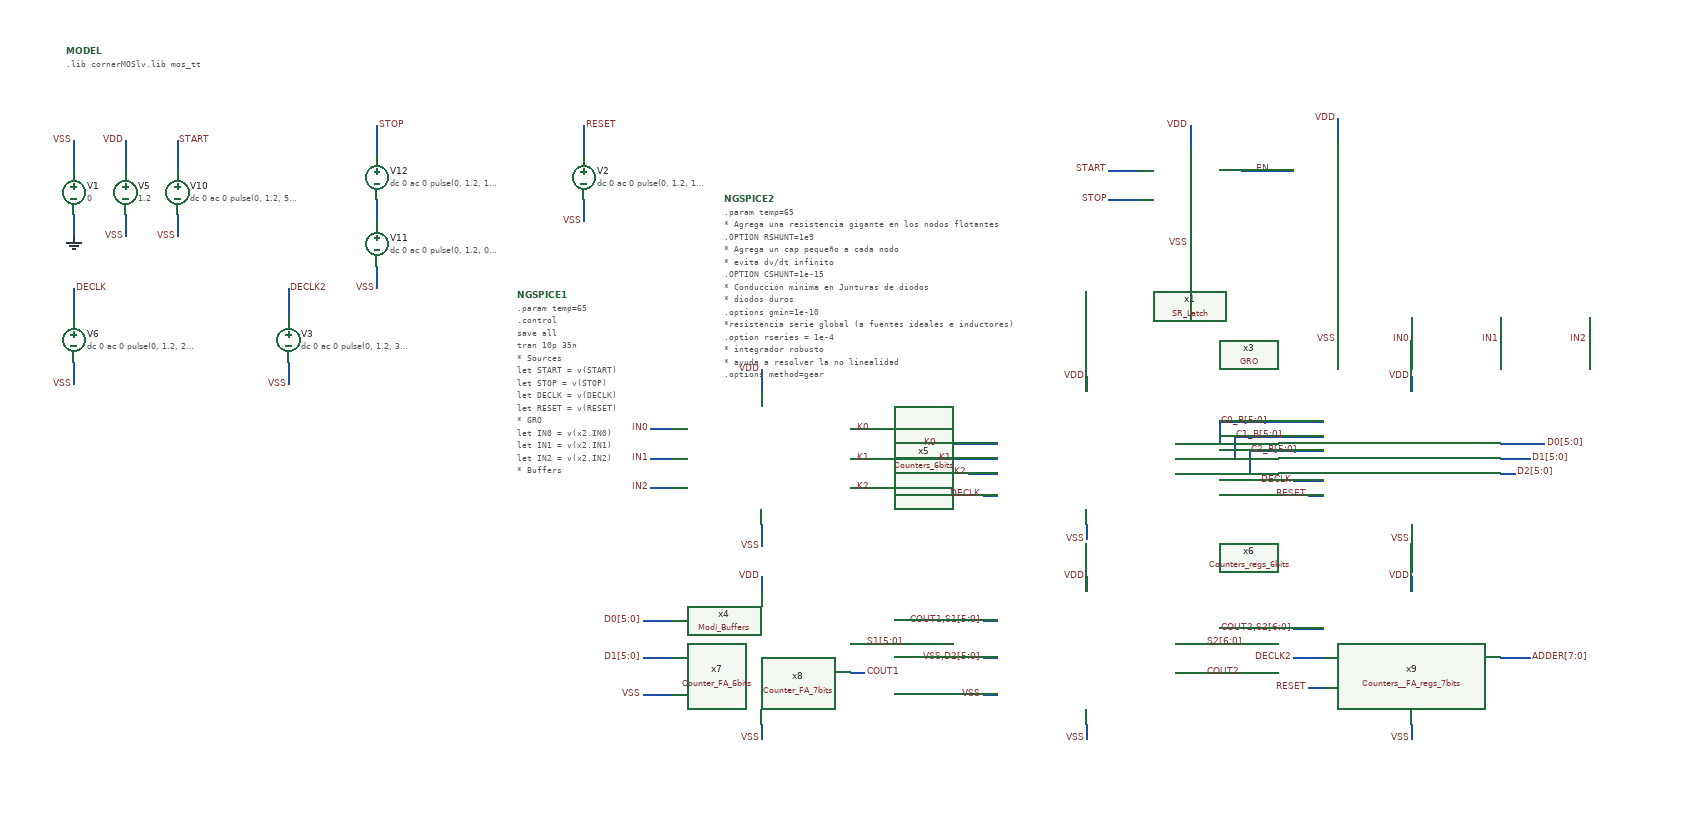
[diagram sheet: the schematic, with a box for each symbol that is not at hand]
v {xschem version=3.4.8RC file_version=1.3}
G {}
K {}
V {}
S {}
F {}
E {}
B 2 2580 1110 3380 1510 {flags=graph
y2=1.5
ypos1=0
ypos2=2
divy=5
subdivy=1
unity=1
x1=5.3243167e-09
divx=5
subdivx=1


dataset=-1
unitx=1
logx=0
logy=0
hilight_wave=0


y1=-0.2
color="17 8 10"
node="IN0
IN1
IN2"
x2=5.0380316e-08}
B 2 2580 1560 3380 1960 {flags=graph
y2=1.5
ypos1=0
ypos2=2
divy=5
subdivy=1
unity=1
x1=5.3243167e-09
x2=5.0380316e-08
divx=5
subdivx=1


dataset=-1
unitx=1
logx=0
logy=0
hilight_wave=0


y1=-0.2
color="17 8 10"
node="K0
K1
K2"}
B 2 2580 670 3380 1070 {flags=graph
y2=1.5
ypos1=0
ypos2=2
divy=5
subdivy=1
unity=1
x1=5.3243167e-09
x2=5.0380316e-08
divx=5
subdivx=1


dataset=-1
unitx=1
logx=0
logy=0
hilight_wave=0


y1=-0.2
color="17 8 10 7 10"
node="START
STOP
DECLK
EN
RESET"}
B 2 2570 -1110 3370 -710 {flags=graph
y1=-0.024
y2=1.3
ypos1=0
ypos2=2
divy=5
subdivy=1
unity=1
x1=5.3243167e-09
x2=5.0380316e-08
divx=5
subdivx=1


dataset=-1
unitx=1
logx=0
logy=0
hilight_wave=0
color="10 11 11"
node="C0_B[1]
C1_B[1]
C2_B[1]"}
B 2 2570 220 3370 620 {flags=graph
y1=-0.4
y2=1.5
ypos1=0
ypos2=2
divy=5
subdivy=1
unity=1
x1=5.3243167e-09
x2=5.0380316e-08
divx=5
subdivx=1


dataset=-1
unitx=1
logx=0
logy=0
hilight_wave=0
color="8 7 11"
node="C0_B[4]
C1_B[4]
C2_B[4]"
rainbow=1}
B 2 2570 -690 3370 -290 {flags=graph
y1=-0.4
y2=1.5
ypos1=0
ypos2=2
divy=5
subdivy=1
unity=1
x1=5.3243167e-09
x2=5.0380316e-08
divx=5
subdivx=1


dataset=-1
unitx=1
logx=0
logy=0
hilight_wave=0
color="7 11 10"
node="C0_B[2]
C1_B[2]
C2_B[2]"}
B 2 2570 -230 3370 170 {flags=graph
y1=-0.032
y2=1.3
ypos1=0
ypos2=2
divy=5
subdivy=1
unity=1
x1=5.3243167e-09
x2=5.0380316e-08
divx=5
subdivx=1


dataset=-1
unitx=1
logx=0
logy=0
hilight_wave=0


color="11 10 7"
node="C0_B[3]
C1_B[3]
C2_B[3]"}
B 2 3400 -1110 4200 -710 {flags=graph
y1=-0.4
y2=1.5
ypos1=0
ypos2=2
divy=5
subdivy=1
unity=1
x1=5.3243167e-09
x2=5.0380316e-08
divx=5
subdivx=1


dataset=-1
unitx=1
logx=0
logy=0
hilight_wave=0
color=10
node=D0[1]}
B 2 3400 -1530 4200 -1130 {flags=graph
y1=-0.4
y2=1.5
ypos1=0
ypos2=2
divy=5
subdivy=1
unity=1
x1=5.3243167e-09
x2=5.0380316e-08
divx=5
subdivx=1


dataset=-1
unitx=1
logx=0
logy=0
hilight_wave=0
color=8
node=D0[0]}
B 2 3400 220 4200 620 {flags=graph
y1=-0.4
y2=1.5
ypos1=0
ypos2=2
divy=5
subdivy=1
unity=1
x1=5.3243167e-09
x2=5.0380316e-08
divx=5
subdivx=1


dataset=-1
unitx=1
logx=0
logy=0
hilight_wave=0
color=8
node=D0[4]}
B 2 3400 -690 4200 -290 {flags=graph
y1=-0.4
y2=1.5
ypos1=0
ypos2=2
divy=5
subdivy=1
unity=1
x1=5.3243167e-09
x2=5.0380316e-08
divx=5
subdivx=1


dataset=-1
unitx=1
logx=0
logy=0
hilight_wave=0
color=7
node=D0[2]}
B 2 3400 -230 4200 170 {flags=graph
y1=-0.4
y2=1.5
ypos1=0
ypos2=2
divy=5
subdivy=1
unity=1
x1=5.3243167e-09
x2=5.0380316e-08
divx=5
subdivx=1


dataset=-1
unitx=1
logx=0
logy=0
hilight_wave=0


color=11
node=D0[3]}
B 2 2570 -1530 3370 -1130 {flags=graph
y1=-0.4
y2=1.5
ypos1=0
ypos2=2
divy=5
subdivy=1
unity=1
x1=5.3243167e-09
x2=5.0380316e-08
divx=5
subdivx=1


dataset=-1
unitx=1
logx=0
logy=0
hilight_wave=0
color="10 11 11"
node="C0_B[0]
C1_B[0]
C2_B[0]"}
B 2 4230 -1110 5030 -710 {flags=graph
y1=-0.4
y2=1.5
ypos1=0
ypos2=2
divy=5
subdivy=1
unity=1
x1=5.3243167e-09
x2=5.0380316e-08
divx=5
subdivx=1


dataset=-1
unitx=1
logx=0
logy=0
hilight_wave=0
color=10
node=D1[1]}
B 2 4230 -1530 5030 -1130 {flags=graph
y1=-0.4
y2=1.5
ypos1=0
ypos2=2
divy=5
subdivy=1
unity=1
x1=5.3243167e-09
x2=5.0380316e-08
divx=5
subdivx=1


dataset=-1
unitx=1
logx=0
logy=0
hilight_wave=0
color=8
node=D1[0]}
B 2 4230 220 5030 620 {flags=graph
y1=-0.4
y2=1.5
ypos1=0
ypos2=2
divy=5
subdivy=1
unity=1
x1=5.3243167e-09
x2=5.0380316e-08
divx=5
subdivx=1


dataset=-1
unitx=1
logx=0
logy=0
hilight_wave=0
color=8
node=D1[4]}
B 2 4230 -690 5030 -290 {flags=graph
y1=-0.4
y2=1.5
ypos1=0
ypos2=2
divy=5
subdivy=1
unity=1
x1=5.3243167e-09
x2=5.0380316e-08
divx=5
subdivx=1


dataset=-1
unitx=1
logx=0
logy=0
hilight_wave=0
color=7
node=D1[2]}
B 2 4230 -230 5030 170 {flags=graph
y1=-0.4
y2=1.5
ypos1=0
ypos2=2
divy=5
subdivy=1
unity=1
x1=5.3243167e-09
x2=5.0380316e-08
divx=5
subdivx=1


dataset=-1
unitx=1
logx=0
logy=0
hilight_wave=0


color=11
node=D1[3]}
B 2 5070 -1110 5870 -710 {flags=graph
y1=-0.4
y2=1.5
ypos1=0
ypos2=2
divy=5
subdivy=1
unity=1
x1=5.3243167e-09
x2=5.0380316e-08
divx=5
subdivx=1


dataset=-1
unitx=1
logx=0
logy=0
hilight_wave=0
color=10
node=D2[1]}
B 2 5070 -1530 5870 -1130 {flags=graph
y1=-0.4
y2=1.5
ypos1=0
ypos2=2
divy=5
subdivy=1
unity=1
x1=5.3243167e-09
x2=5.0380316e-08
divx=5
subdivx=1


dataset=-1
unitx=1
logx=0
logy=0
hilight_wave=0
color=8
node=D2[0]}
B 2 5070 220 5870 620 {flags=graph
y1=-0.4
y2=1.5
ypos1=0
ypos2=2
divy=5
subdivy=1
unity=1
x1=5.3243167e-09
x2=5.0380316e-08
divx=5
subdivx=1


dataset=-1
unitx=1
logx=0
logy=0
hilight_wave=0
color=8
node=D2[4]}
B 2 5070 -690 5870 -290 {flags=graph
y1=-0.4
y2=1.5
ypos1=0
ypos2=2
divy=5
subdivy=1
unity=1
x1=5.3243167e-09
x2=5.0380316e-08
divx=5
subdivx=1


dataset=-1
unitx=1
logx=0
logy=0
hilight_wave=0
color=7
node=D2[2]}
B 2 5070 -230 5870 170 {flags=graph
y1=-0.4
y2=1.5
ypos1=0
ypos2=2
divy=5
subdivy=1
unity=1
x1=5.3243167e-09
x2=5.0380316e-08
divx=5
subdivx=1


dataset=-1
unitx=1
logx=0
logy=0
hilight_wave=0


color=11
node=D2[3]}
B 2 5910 -1110 6710 -710 {flags=graph
y1=-0.4
y2=1.5
ypos1=0
ypos2=2
divy=5
subdivy=1
unity=1
x1=5.3243167e-09
x2=5.0380316e-08
divx=5
subdivx=1


dataset=-1
unitx=1
logx=0
logy=0
hilight_wave=0
color=10
node=S1[1]}
B 2 5910 -1530 6710 -1130 {flags=graph
y1=-0.4
y2=1.5
ypos1=0
ypos2=2
divy=5
subdivy=1
unity=1
x1=5.3243167e-09
x2=5.0380316e-08
divx=5
subdivx=1


dataset=-1
unitx=1
logx=0
logy=0
hilight_wave=-1
color=8
node=S1[0]}
B 2 5910 220 6710 620 {flags=graph
y1=-0.4
y2=1.5
ypos1=0
ypos2=2
divy=5
subdivy=1
unity=1
x1=5.3243167e-09
x2=5.0380316e-08
divx=5
subdivx=1


dataset=-1
unitx=1
logx=0
logy=0
hilight_wave=0
color=8
node=S1[4]}
B 2 5910 640 6710 1040 {flags=graph
y2=1.5
ypos1=0
ypos2=2
divy=5
subdivy=1
unity=1
x1=5.3243167e-09
x2=5.0380316e-08
divx=5
subdivx=1


dataset=-1
unitx=1
logx=0
logy=0
hilight_wave=0
color=10
node=S1[5]
y1=-0.4}
B 2 5910 -690 6710 -290 {flags=graph
y1=-0.4
y2=1.5
ypos1=0
ypos2=2
divy=5
subdivy=1
unity=1
x1=5.3243167e-09
x2=5.0380316e-08
divx=5
subdivx=1


dataset=-1
unitx=1
logx=0
logy=0
hilight_wave=0
color=7
node=S1[2]}
B 2 5910 -230 6710 170 {flags=graph
y1=-0.4
y2=1.5
ypos1=0
ypos2=2
divy=5
subdivy=1
unity=1
x1=5.3243167e-09
x2=5.0380316e-08
divx=5
subdivx=1


dataset=-1
unitx=1
logx=0
logy=0
hilight_wave=0


color=11
node=S1[3]}
B 2 6750 -1110 7550 -710 {flags=graph
y1=-0.4
y2=1.5
ypos1=0
ypos2=2
divy=5
subdivy=1
unity=1
x1=5.3243167e-09
x2=5.0380316e-08
divx=5
subdivx=1


dataset=-1
unitx=1
logx=0
logy=0
hilight_wave=0
color=10
node=S2[1]}
B 2 6750 -1530 7550 -1130 {flags=graph
y1=-0.4
y2=1.5
ypos1=0
ypos2=2
divy=5
subdivy=1
unity=1
x1=5.3243167e-09
x2=5.0380316e-08
divx=5
subdivx=1


dataset=-1
unitx=1
logx=0
logy=0
hilight_wave=0
color=8
node=S2[0]}
B 2 6750 220 7550 620 {flags=graph
y1=-0.4
y2=1.5
ypos1=0
ypos2=2
divy=5
subdivy=1
unity=1
x1=5.3243167e-09
x2=5.0380316e-08
divx=5
subdivx=1


dataset=-1
unitx=1
logx=0
logy=0
hilight_wave=0
color=8
node=S2[4]}
B 2 6750 640 7550 1040 {flags=graph
y2=1.5
ypos1=0
ypos2=2
divy=5
subdivy=1
unity=1
x1=5.3243167e-09
x2=5.0380316e-08
divx=5
subdivx=1


dataset=-1
unitx=1
logx=0
logy=0
hilight_wave=0
color=10
node=S2[5]
y1=-0.4}
B 2 6750 -690 7550 -290 {flags=graph
y1=-0.4
y2=1.5
ypos1=0
ypos2=2
divy=5
subdivy=1
unity=1
x1=5.3243167e-09
x2=5.0380316e-08
divx=5
subdivx=1


dataset=-1
unitx=1
logx=0
logy=0
hilight_wave=-1
color=7
node=S2[2]}
B 2 6750 -230 7550 170 {flags=graph
y1=-0.4
y2=1.5
ypos1=0
ypos2=2
divy=5
subdivy=1
unity=1
x1=5.3243167e-09
x2=5.0380316e-08
divx=5
subdivx=1


dataset=-1
unitx=1
logx=0
logy=0
hilight_wave=0


color=11
node=S2[3]}
B 2 6750 1090 7550 1490 {flags=graph
y2=1.5
ypos1=0
ypos2=2
divy=5
subdivy=1
unity=1
x1=5.3243167e-09
x2=5.0380316e-08
divx=5
subdivx=1


dataset=-1
unitx=1
logx=0
logy=0
hilight_wave=0
y1=-0.4
color=10
node=S2[6]}
B 2 6760 1540 7560 1940 {flags=graph
y2=1.5
ypos1=0
ypos2=2
divy=5
subdivy=1
unity=1
x1=5.3243167e-09
x2=5.0380316e-08
divx=5
subdivx=1


dataset=-1
unitx=1
logx=0
logy=0
hilight_wave=0
y1=-0.4
color=10
node=COUT2}
B 2 7630 -1110 8430 -710 {flags=graph
y1=-0.4
y2=1.5
ypos1=0
ypos2=2
divy=5
subdivy=1
unity=1
x1=5.3243167e-09
x2=5.0380316e-08
divx=5
subdivx=1


dataset=-1
unitx=1
logx=0
logy=0
hilight_wave=0
color=10
node=ADDER[1]}
B 2 7630 -1530 8430 -1130 {flags=graph
y1=-0.4
y2=1.5
ypos1=0
ypos2=2
divy=5
subdivy=1
unity=1
x1=5.3243167e-09
x2=5.0380316e-08
divx=5
subdivx=1


dataset=-1
unitx=1
logx=0
logy=0
hilight_wave=0
color=8
node=ADDER[0]}
B 2 7630 220 8430 620 {flags=graph
y1=-0.4
y2=1.5
ypos1=0
ypos2=2
divy=5
subdivy=1
unity=1
x1=5.3243167e-09
x2=5.0380316e-08
divx=5
subdivx=1


dataset=-1
unitx=1
logx=0
logy=0
hilight_wave=0
color=8
node=ADDER[4]}
B 2 7630 640 8430 1040 {flags=graph
y2=1.5
ypos1=0
ypos2=2
divy=5
subdivy=1
unity=1
x1=5.3243167e-09
x2=5.0380316e-08
divx=5
subdivx=1


dataset=-1
unitx=1
logx=0
logy=0
hilight_wave=0
color=10
node=ADDER[5]
y1=-0.4}
B 2 7630 -690 8430 -290 {flags=graph
y1=-0.4
y2=1.5
ypos1=0
ypos2=2
divy=5
subdivy=1
unity=1
x1=5.3243167e-09
x2=5.0380316e-08
divx=5
subdivx=1


dataset=-1
unitx=1
logx=0
logy=0
hilight_wave=0
color=7
node=ADDER[2]}
B 2 7630 -230 8430 170 {flags=graph
y1=-0.4
y2=1.5
ypos1=0
ypos2=2
divy=5
subdivy=1
unity=1
x1=5.3243167e-09
x2=5.0380316e-08
divx=5
subdivx=1


dataset=-1
unitx=1
logx=0
logy=0
hilight_wave=0


color=11
node=ADDER[3]}
B 2 7630 1090 8430 1490 {flags=graph
y2=1.5
ypos1=0
ypos2=2
divy=5
subdivy=1
unity=1
x1=5.3243167e-09
x2=5.0380316e-08
divx=5
subdivx=1


dataset=-1
unitx=1
logx=0
logy=0
hilight_wave=0
y1=-0.4
color=10
node=ADDER[6]}
B 2 7630 1540 8430 1940 {flags=graph
y2=1.5
ypos1=0
ypos2=2
divy=5
subdivy=1
unity=1
x1=5.3243167e-09
x2=5.0380316e-08
divx=5
subdivx=1


dataset=-1
unitx=1
logx=0
logy=0
hilight_wave=0
y1=-0.4
color=10
node=ADDER[7]}
B 2 1680 670 2480 1070 {flags=graph
y2=1.5
ypos1=0
ypos2=2
divy=5
subdivy=1
unity=1
x1=5.3243167e-09
x2=5.0380316e-08
divx=5
subdivx=1


dataset=-1
unitx=1
logx=0
logy=0
hilight_wave=0


y1=-0.2
color="17 7"
node="DECLK
DECLK2"}
N 3620 990 3620 1020 {lab=GND}
N 3620 890 3620 930 {lab=VSS}
N 3690 990 3690 1020 {lab=VSS}
N 3690 890 3690 930 {lab=VDD}
N 4310 970 4310 1000 {lab=VSS}
N 3620 1190 3620 1220 {lab=VSS}
N 4310 870 4310 910 {lab=RESET}
N 3620 1090 3620 1130 {lab=DECLK}
N 4030 1060 4030 1090 {lab=VSS}
N 3760 990 3760 1020 {lab=VSS}
N 4030 870 4030 910 {lab=STOP}
N 3760 890 3760 930 {lab=START}
N 4030 970 4030 1000 {lab=#net1}
N 4990 1210 4990 1230 {lab=VDD}
N 5430 1210 5430 1230 {lab=VDD}
N 4990 1410 4990 1430 {lab=VSS}
N 5430 1410 5430 1430 {lab=VSS}
N 4550 1480 4550 1500 {lab=VDD}
N 4990 1480 4990 1500 {lab=VDD}
N 4550 1680 4550 1700 {lab=VSS}
N 4990 1680 4990 1700 {lab=VSS}
N 5110 1570 5150 1570 {lab=S2[6:0]}
N 5110 1610 5150 1610 {lab=COUT2}
N 5550 1300 5610 1300 {lab=D0[5:0]}
N 5550 1320 5590 1320 {lab=D1[5:0]}
N 5550 1340 5570 1340 {lab=D2[5:0]}
N 5270 1350 5310 1350 {lab=DECLK}
N 5290 1370 5310 1370 {lab=RESET}
N 5110 1300 5170 1300 {lab=C0_B[5:0]}
N 5110 1320 5190 1320 {lab=C1_B[5:0]}
N 5110 1340 5210 1340 {lab=C2_B[5:0]}
N 4850 1370 4870 1370 {lab=DECLK}
N 4830 1340 4870 1340 {lab=K2}
N 4810 1320 4870 1320 {lab=K1}
N 4790 1300 4870 1300 {lab=K0}
N 4390 1540 4430 1540 {lab=D0[5:0]}
N 4390 1590 4430 1590 {lab=D1[5:0]}
N 4390 1640 4430 1640 {lab=VSS}
N 5170 1270 5170 1300 {lab=C0_B[5:0]}
N 5170 1270 5310 1270 {lab=C0_B[5:0]}
N 5190 1290 5190 1320 {lab=C1_B[5:0]}
N 5190 1290 5310 1290 {lab=C1_B[5:0]}
N 5210 1310 5210 1340 {lab=C2_B[5:0]}
N 5210 1310 5310 1310 {lab=C2_B[5:0]}
N 4670 1570 4690 1570 {lab=S1[5:0]}
N 4670 1610 4690 1610 {lab=COUT1}
N 4850 1640 4870 1640 {lab=VSS}
N 4850 1590 4870 1590 {lab=VSS,D2[5:0]}
N 4850 1540 4870 1540 {lab=COUT1,S1[5:0]}
N 5430 1480 5430 1500 {lab=VDD}
N 5430 1680 5430 1700 {lab=VSS}
N 5550 1590 5590 1590 {lab=ADDER[7:0]}
N 5290 1630 5310 1630 {lab=RESET}
N 5270 1590 5310 1590 {lab=DECLK2}
N 5270 1550 5310 1550 {lab=COUT2,S2[6:0]}
N 5020 930 5060 930 {lab=START}
N 5020 970 5060 970 {lab=STOP}
N 5130 870 5130 900 {lab=VDD}
N 5130 1000 5130 1030 {lab=VSS}
N 5330 860 5330 890 {lab=VDD}
N 5200 930 5270 930 {lab=EN}
N 5330 1130 5330 1160 {lab=VSS}
N 5430 1130 5430 1160 {lab=IN0}
N 5550 1130 5550 1160 {lab=IN1}
N 5670 1130 5670 1160 {lab=IN2}
N 4550 1410 4550 1440 {lab=VSS}
N 4670 1280 4700 1280 {lab=K0}
N 4670 1320 4700 1320 {lab=K1}
N 4670 1360 4700 1360 {lab=K2}
N 4400 1280 4430 1280 {lab=IN0}
N 4400 1320 4430 1320 {lab=IN1}
N 4400 1360 4430 1360 {lab=IN2}
N 4550 1200 4550 1230 {lab=VDD}
N 3910 1190 3910 1220 {lab=VSS}
N 3910 1090 3910 1130 {lab=DECLK2}
C {vsource.sym} 3620 960 0 0 {name=V1 value=0 savecurrent=false
}
C {gnd.sym} 3620 1020 0 0 {name=l1 lab=GND
}
C {lab_wire.sym} 3620 890 0 0 {name=p1 sig_type=std_logic lab=VSS
}
C {vsource.sym} 3690 960 0 0 {name=V5 value=1.2 savecurrent=false
}
C {lab_wire.sym} 3690 1020 0 0 {name=p2 sig_type=std_logic lab=VSS
}
C {devices/launcher.sym} 4065 815 0 0 {name=h5
descr="load waves Ctrl + left click" 
tclcommand="xschem raw_read $netlist_dir/GRO_TDC_tb.raw tran"
}
C {devices/launcher.sym} 4065 755 0 0 {name=h1
descr="simulate" 
tclcommand="xschem save; xschem netlist; xschem simulate"
}
C {devices/code_shown.sym} 3610 770 0 0 {name=MODEL only_toplevel=true
format="tcleval( @value )"
value="
.lib cornerMOSlv.lib mos_tt
"}
C {vsource.sym} 4310 940 0 0 {name=V2 value="dc 0 ac 0 pulse(0, 1.2, 190n, 500p, 500p, 5n, 0)" savecurrent=false
}
C {lab_wire.sym} 3620 1220 0 0 {name=p3 sig_type=std_logic lab=VSS
}
C {lab_wire.sym} 4310 870 0 1 {name=p6 sig_type=std_logic lab=RESET
}
C {lab_wire.sym} 3620 1090 0 1 {name=p4 sig_type=std_logic lab=DECLK
}
C {vsource.sym} 3620 1160 0 0 {name=V6 value="dc 0 ac 0 pulse(0, 1.2, 27n, 500p, 500p, 100n)" savecurrent=false
}
C {lab_wire.sym} 3690 890 0 0 {name=p5 sig_type=std_logic lab=VDD
}
C {lab_wire.sym} 4310 1000 0 0 {name=p49 sig_type=std_logic lab=VSS
}
C {lab_wire.sym} 3760 1020 0 0 {name=p54 sig_type=std_logic lab=VSS
}
C {lab_wire.sym} 4030 870 0 1 {name=p55 sig_type=std_logic lab=STOP
}
C {lab_wire.sym} 3760 890 0 1 {name=p56 sig_type=std_logic lab=START
}
C {vsource.sym} 3760 960 0 0 {name=V10 value="dc 0 ac 0 pulse(0, 1.2, 5n, 50p, 50p, 21n)" savecurrent=false
}
C {vsource.sym} 4030 1030 0 0 {name=V11 value="dc 0 ac 0 pulse(0, 1.2, 0, 50p, 50p, 1n, 0)" savecurrent=false
}
C {vsource.sym} 4030 940 0 0 {name=V12 value="dc 0 ac 0 pulse(0, 1.2, 14n, 50p, 50p, 100n)" savecurrent=false
}
C {lab_wire.sym} 4030 1090 0 0 {name=p60 sig_type=std_logic lab=VSS
}
C {code.sym} 4220 1100 0 0 {name=NGSPICE1 only_toplevel=true 
value="
.param temp=65


.control
save all 
tran 10p 35n
* Sources
let START = v(START)
let STOP = v(STOP)
let DECLK = v(DECLK)
let RESET = v(RESET)

* GRO
let IN0 = v(x2.IN0)
let IN1 = v(x2.IN1)
let IN2 = v(x2.IN2)

* Buffers
let K0 = v(x2.K0)
let K1 = v(x2.K1)
let K2 = v(x2.K2)

* Counters Reg
let D0_0 = v(x2.D0[0])
let D0_1 = v(x2.D0[1])
let D0_2 = v(x2.D0[2])
let D0_3 = v(x2.D0[3])
let D0_4 = v(x2.D0[4])
let D0_5 = v(x2.D0[5])
let D1_0 = v(x2.D1[0])
let D1_1 = v(x2.D1[1])
let D1_2 = v(x2.D1[2])
let D1_3 = v(x2.D1[3])
let D1_4 = v(x2.D1[4])
let D1_5 = v(x2.D1[5])
let D2_0 = v(x2.D2[0])
let D2_1 = v(x2.D2[1])
let D2_2 = v(x2.D2[2])
let D2_3 = v(x2.D2[3])
let D2_4 = v(x2.D2[4])
let D2_5 = v(x2.D2[5])

* FA
let S1_0 = v(x2.S1[0])
let S1_1 = v(x2.S1[1])
let S1_2 = v(x2.S1[2])
let S1_3 = v(x2.S1[3])
let S1_4 = v(x2.S1[4])
let S1_5 = v(x2.S1[5])
let COUT1 = v(x2.COUT1)
let S2_0 = v(x2.S2[0])
let S2_1 = v(x2.S2[1])
let S2_2 = v(x2.S2[2])
let S2_3 = v(x2.S2[3])
let S2_4 = v(x2.S2[4])
let S2_5 = v(x2.S2[5])
let S2_6 = v(x2.S2[6])
let COUT2 = v(x2.COUT2)

* FA Regs
let ADDER_0 = v(x2.ADDER[0])
let ADDER_1 = v(x2.ADDER[1])
let ADDER_2 = v(x2.ADDER[2])
let ADDER_3 = v(x2.ADDER[3])
let ADDER_4 = v(x2.ADDER[4])
let ADDER_5 = v(x2.ADDER[5])
let ADDER_6 = v(x2.ADDER[6])
let ADDER_7 = v(x2.ADDER[7])

write GROTDC_tb.raw
wrdata GRO_TDC_tb.raw time START STOP DECLK RESET IN0 IN1 IN2 K0 K1 K2 D0_0 D0_1 D0_2 D0_3 D0_4 D0_5 D1_0 D1_1 D1_2 D1_3 D1_4 D1_5 D2_0 D2_1 D2_2 D2_3 D2_4 D2_5 S1_0 S1_1 S1_2 S1_3 S1_4 S1_5 COUT1 S2_0 S2_1 S2_2 S2_3 S2_4 S2_5 S2_6 COUT2 ADDER_0 ADDER_1 ADDER_2 ADDER_3 ADDER_4 ADDER_5 ADDER_6  ADDER_7


*set appendwrite

.endc
"
spice_ignore=true}
C {Counters_6bits.sym} 4770 1470 0 0 {name=x5
}
C {Counters_regs_6bits.sym} 5210 1500 0 0 {name=x6
}
C {Counter_FA_6bits.sym} 4410 1680 0 0 {name=x7
}
C {Counter_FA_7bits.sym} 4610 1760 0 0 {name=x8
}
C {lab_wire.sym} 4990 1430 0 0 {name=p9 sig_type=std_logic lab=VSS
}
C {lab_wire.sym} 5430 1430 0 0 {name=p10 sig_type=std_logic lab=VSS
}
C {lab_wire.sym} 4990 1700 0 0 {name=p11 sig_type=std_logic lab=VSS
}
C {lab_wire.sym} 4550 1700 0 0 {name=p12 sig_type=std_logic lab=VSS
}
C {lab_wire.sym} 4990 1210 0 0 {name=p13 sig_type=std_logic lab=VDD
}
C {lab_wire.sym} 5430 1210 0 0 {name=p14 sig_type=std_logic lab=VDD
}
C {lab_wire.sym} 4990 1480 0 0 {name=p15 sig_type=std_logic lab=VDD
}
C {lab_wire.sym} 4550 1480 0 0 {name=p16 sig_type=std_logic lab=VDD
}
C {lab_wire.sym} 4810 1320 3 0 {name=p18 sig_type=std_logic lab=K1
}
C {lab_wire.sym} 4790 1300 3 0 {name=p17 sig_type=std_logic lab=K0
}
C {lab_wire.sym} 4830 1340 3 0 {name=p19 sig_type=std_logic lab=K2
}
C {lab_wire.sym} 4850 1370 3 0 {name=p20 sig_type=std_logic lab=DECLK
}
C {lab_wire.sym} 5270 1350 3 0 {name=p21 sig_type=std_logic lab=DECLK
}
C {lab_wire.sym} 5290 1370 3 0 {name=p22 sig_type=std_logic lab=RESET
}
C {lab_wire.sym} 4850 1540 0 0 {name=p23 sig_type=std_logic lab=COUT1,S1[5:0]
}
C {lab_wire.sym} 5610 1300 0 1 {name=p24 sig_type=std_logic lab=D0[5:0]
}
C {lab_wire.sym} 5590 1320 0 1 {name=p25 sig_type=std_logic lab=D1[5:0]
}
C {lab_wire.sym} 5570 1340 0 1 {name=p26 sig_type=std_logic lab=D2[5:0]
}
C {lab_wire.sym} 4390 1540 0 0 {name=p27 sig_type=std_logic lab=D0[5:0]
}
C {lab_wire.sym} 4390 1590 0 0 {name=p28 sig_type=std_logic lab=D1[5:0]
}
C {lab_wire.sym} 4850 1590 0 0 {name=p29 sig_type=std_logic lab=VSS,D2[5:0]
}
C {lab_wire.sym} 4390 1640 0 0 {name=p30 sig_type=std_logic lab=VSS
}
C {lab_wire.sym} 4850 1640 0 0 {name=p31 sig_type=std_logic lab=VSS
}
C {lab_wire.sym} 4690 1570 0 1 {name=p32 sig_type=std_logic lab=S1[5:0]
}
C {lab_wire.sym} 4690 1610 0 1 {name=p33 sig_type=std_logic lab=COUT1
}
C {lab_wire.sym} 5150 1610 0 1 {name=p35 sig_type=std_logic lab=COUT2
}
C {lab_wire.sym} 5430 1480 0 0 {name=p36 sig_type=std_logic lab=VDD
}
C {lab_wire.sym} 5430 1700 0 0 {name=p37 sig_type=std_logic lab=VSS
}
C {lab_wire.sym} 5270 1590 3 0 {name=p34 sig_type=std_logic lab=DECLK2
}
C {lab_wire.sym} 5290 1630 3 0 {name=p38 sig_type=std_logic lab=RESET
}
C {Counters__FA_regs_7bits.sym} 5270 1710 0 0 {name=x9
}
C {lab_wire.sym} 5590 1590 0 1 {name=p39 sig_type=std_logic lab=ADDER[7:0]
}
C {lab_wire.sym} 5150 1570 0 1 {name=p7 sig_type=std_logic lab=S2[6:0]
}
C {lab_wire.sym} 5270 1550 0 0 {name=p8 sig_type=std_logic lab=COUT2,S2[6:0]
}
C {lab_wire.sym} 5130 1030 0 0 {name=p43 sig_type=std_logic lab=VSS
}
C {lab_wire.sym} 5330 860 0 0 {name=p44 sig_type=std_logic lab=VDD
}
C {SR_Latch.sym} 5040 1040 0 0 {name=x1}
C {lab_wire.sym} 5130 870 0 0 {name=p61 sig_type=std_logic lab=VDD
}
C {lab_wire.sym} 5020 930 0 0 {name=p62 sig_type=std_logic lab=START
}
C {lab_wire.sym} 5020 970 0 0 {name=p63 sig_type=std_logic lab=STOP
}
C {lab_wire.sym} 5240 930 0 0 {name=p64 sig_type=std_logic lab=EN
}
C {GRO.sym} 5270 1150 0 0 {name=x3
}
C {lab_wire.sym} 5330 1160 0 0 {name=p65 sig_type=std_logic lab=VSS
}
C {lab_wire.sym} 5430 1160 0 0 {name=p66 sig_type=std_logic lab=IN0
}
C {lab_wire.sym} 5550 1160 0 0 {name=p67 sig_type=std_logic lab=IN1
}
C {lab_wire.sym} 5670 1160 0 0 {name=p68 sig_type=std_logic lab=IN2
}
C {lab_wire.sym} 4550 1440 0 0 {name=p69 sig_type=std_logic lab=VSS
}
C {Modi_Buffers.sym} 4330 1500 0 0 {name=x4
}
C {lab_wire.sym} 4700 1280 3 1 {name=p70 sig_type=std_logic lab=K0
}
C {lab_wire.sym} 4700 1320 3 1 {name=p71 sig_type=std_logic lab=K1
}
C {lab_wire.sym} 4700 1360 3 1 {name=p72 sig_type=std_logic lab=K2
}
C {lab_wire.sym} 4400 1280 1 0 {name=p73 sig_type=std_logic lab=IN0
}
C {lab_wire.sym} 4400 1320 1 0 {name=p74 sig_type=std_logic lab=IN1
}
C {lab_wire.sym} 4400 1360 1 0 {name=p75 sig_type=std_logic lab=IN2
}
C {lab_wire.sym} 4550 1200 0 0 {name=p76 sig_type=std_logic lab=VDD
}
C {lab_wire.sym} 5170 1270 0 1 {name=p40 sig_type=std_logic lab=C0_B[5:0]
}
C {lab_wire.sym} 5190 1290 0 1 {name=p41 sig_type=std_logic lab=C1_B[5:0]
}
C {lab_wire.sym} 5210 1310 0 1 {name=p42 sig_type=std_logic lab=C2_B[5:0]
}
C {lab_wire.sym} 3910 1220 0 0 {name=p45 sig_type=std_logic lab=VSS
}
C {lab_wire.sym} 3910 1090 0 1 {name=p46 sig_type=std_logic lab=DECLK2
}
C {vsource.sym} 3910 1160 0 0 {name=V3 value="dc 0 ac 0 pulse(0, 1.2, 30n, 500p, 500p, 100n)" savecurrent=false
}
C {code.sym} 4500 970 0 0 {name=NGSPICE2 only_toplevel=true 
value="
.param temp=65

* Agrega una resistencia gigante en los nodos flotantes
.OPTION RSHUNT=1e9

* Agrega un cap pequeño a cada nodo
* evita dv/dt infinito
.OPTION CSHUNT=1e-15

* Conducción minima en Junturas de diodos
* diodos duros
.options gmin=1e-10

*resistencia serie global (a fuentes ideales e inductores)
.option rseries = 1e-4

* integrador robusto
* ayuda a resolver la no linealidad
.options method=gear

* limita el orden del integrador
* limita cuantos pasos anteriores usa el integrador
.options maxord=2

* tolerancias : error relativo (%) - error absoluto en voltaje - error absoluto en corriente
.options reltol=1e-2 vabstol=1e-4 iabstol=1e-9

* paciencia del solver: DC - Transitorio - Newton interno

.option ITL1=1000 ITL2=400 ITL4=500




* .nodeset all=0
.ic v(START)=0 v(STOP)=0 v(DECLK)=0 v(DECLK2)=0 v(RESET)=0


.ic v(IN0) v(IN1) v(IN2)
.ic v(K0) v(K1) v(K2)
.ic v("D0[0]")=0 v("D0[1]")=0 v("D0[2]")=0 
.ic v("D0[3]")=0 v("D0[4]")=0 v("D0[5]")=0 
.ic v("D1[0]")=0 v("D1[1]")=0 v("D1[2]")=0
.ic v("D1[3]")=0 v("D1[4]")=0 v("D1[5]")=0
.ic v("D2[0]")=0 v("D2[1]")=0 v("D2[2]")=0
.ic v("D2[3]")=0 v("D2[4]")=0 v("D2[5]")=0
.ic v("C0_B[0]")=0 v("C1_B[0]")=0 v("C2_B[0]")=0
.ic v("C0_B[1]")=0 v("C1_B[1]")=0 v("C2_B[1]")=0
.ic v("C0_B[2]")=0 v("C1_B[2]")=0 v("C2_B[2]")=0
.ic v("C0_B[3]")=0 v("C1_B[3]")=0 v("C2_B[3]")=0
.ic v("C0_B[4]")=0 v("C1_B[4]")=0 v("C2_B[4]")=0
.ic v("C0_B[5]")=0 v("C1_B[5]")=0 v("C2_B[5]")=0
.ic v("S1[0]")=0 v("S1[1]")=0 v("S1[2]")=0 
.ic v("S1[3]")=0 v("S1[4]")=0 v("S1[5]")=0 
.ic v(COUT1)=0 
.ic v("S2[0]")=0 v("S2[1]")=0 v("S2[2]")=0 
.ic v("S2[3]")=0 v("S2[4]")=0 v("S2[5]") v("S2[6]")=0
.ic v(COUT2)=0
.ic v("ADDER[0]")=0 v("ADDER[1]")=0 v("ADDER[2]")=0
.ic v("ADDER[3]")=0 v("ADDER[4]")=0 v("ADDER[5]")=0
.ic v("ADDER[6]")=0 v("ADDER[7]")=0

.control
* Sources
save v(START) v(STOP) v(DECLK) v(DECLK2) v(RESET)
save v(START_PAD) v(STOP_PAD) v(RESET_PAD)
save v(VSS) v(VDD) v(EN)

* GRO
save v(IN0) v(IN1) v(IN2)

* Buffers
save v(K0) v(K1) v(K2)

* Counters Reg (BUS → SIEMPRE con comillas)
save v("D0[0]") v("D0[1]") v("D0[2]") 
save v("D0[3]") v("D0[4]") v("D0[5]") 
save v("D1[0]") v("D1[1]") v("D1[2]")
save v("D1[3]") v("D1[4]") v("D1[5]")
save v("D2[0]") v("D2[1]") v("D2[2]")
save v("D2[3]") v("D2[4]") v("D2[5]")


* NUEVO: C0_B[4], C1_B[4], C2_B[4] (bits 0 a 5)
save v("C0_B[0]") v("C1_B[0]") v("C2_B[0]")
save v("C0_B[1]") v("C1_B[1]") v("C2_B[1]")
save v("C0_B[2]") v("C1_B[2]") v("C2_B[2]")
save v("C0_B[3]") v("C1_B[3]") v("C2_B[3]")
save v("C0_B[4]") v("C1_B[4]") v("C2_B[4]")
save v("C0_B[5]") v("C1_B[5]") v("C2_B[5]")



* FA
save v("S1[0]") v("S1[1]") v("S1[2]") 
save v("S1[3]") v("S1[4]") v("S1[5]") 
save v(COUT1) 
save v("S2[0]") v("S2[1]") v("S2[2]") 
save v("S2[3]") v("S2[4]") v("S2[5]") v("S2[6]")
save v(COUT2)

* FA Regs
save v("ADDER[0]") v("ADDER[1]") v("ADDER[2]")
save v("ADDER[3]") v("ADDER[4]") v("ADDER[5]")
save v("ADDER[6]") v("ADDER[7]")

* uic: saltearse el punto de operación
*tran 5p 100n 0 5p uic
* .tran <tstep> <tstop> [tstart] [tmax] [uic]
* tmax Limita el paso máximo que puede usar el integrador
tran 10p 110n 0 95p

write GRO_TDC_tb.raw

.endc
"
}
